# Minimal LEF for testing filler placement with a cell lacking an implant layer

VERSION 5.6 ;
BUSBITCHARS "[]" ;
DIVIDERCHAR "/" ;

UNITS
  DATABASE MICRONS 2000 ;
END UNITS

MANUFACTURINGGRID 0.0050 ;

LAYER RVT
  TYPE IMPLANT ;
END RVT

LAYER metal1
  TYPE ROUTING ;
  SPACING 0.065 ;
  WIDTH 0.07 ;
  PITCH 0.14 ;
  DIRECTION HORIZONTAL ;
END metal1

SITE FreePDK45_38x28_10R_NP_162NW_34O
  SYMMETRY y ;
  CLASS core ;
  SIZE 0.19 BY 1.4 ;
END FreePDK45_38x28_10R_NP_162NW_34O

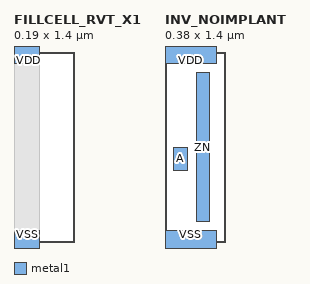
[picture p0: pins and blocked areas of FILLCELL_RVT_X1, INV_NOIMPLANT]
MACRO FILLCELL_RVT_X1
  CLASS CORE SPACER ;
  ORIGIN 0 0 ;
  SIZE 0.19 BY 1.4 ;
  SYMMETRY X Y ;
  SITE FreePDK45_38x28_10R_NP_162NW_34O ;
  PIN VDD
    DIRECTION INOUT ;
    USE POWER ;
    SHAPE ABUTMENT ;
    PORT
      LAYER metal1 ;
        RECT 0 1.315 0.19 1.485 ;
    END
  END VDD
  PIN VSS
    DIRECTION INOUT ;
    USE GROUND ;
    SHAPE ABUTMENT ;
    PORT
      LAYER metal1 ;
        RECT 0 -0.085 0.19 0.085 ;
    END
  END VSS
  OBS
    LAYER RVT ;
      RECT 0 0 0.19 1.4 ;
  END
END FILLCELL_RVT_X1

MACRO INV_NOIMPLANT
  CLASS CORE ;
  ORIGIN 0 0 ;
  SIZE 0.38 BY 1.4 ;
  SYMMETRY X Y ;
  SITE FreePDK45_38x28_10R_NP_162NW_34O ;
  PIN A
    DIRECTION INPUT ;
    USE SIGNAL ;
    PORT
      LAYER metal1 ;
        RECT 0.06 0.525 0.165 0.7 ;
    END
  END A
  PIN ZN
    DIRECTION OUTPUT ;
    USE SIGNAL ;
    PORT
      LAYER metal1 ;
        RECT 0.23 0.15 0.325 1.25 ;
    END
  END ZN
  PIN VDD
    DIRECTION INOUT ;
    USE POWER ;
    SHAPE ABUTMENT ;
    PORT
      LAYER metal1 ;
        RECT 0 1.315 0.38 1.485 ;
    END
  END VDD
  PIN VSS
    DIRECTION INOUT ;
    USE GROUND ;
    SHAPE ABUTMENT ;
    PORT
      LAYER metal1 ;
        RECT 0 -0.085 0.38 0.085 ;
    END
  END VSS
END INV_NOIMPLANT

END LIBRARY
